One B-rep face of a CAD part: STEP entity #4951.
In plain terms, the planar face has unit normal (0, 1, 0).
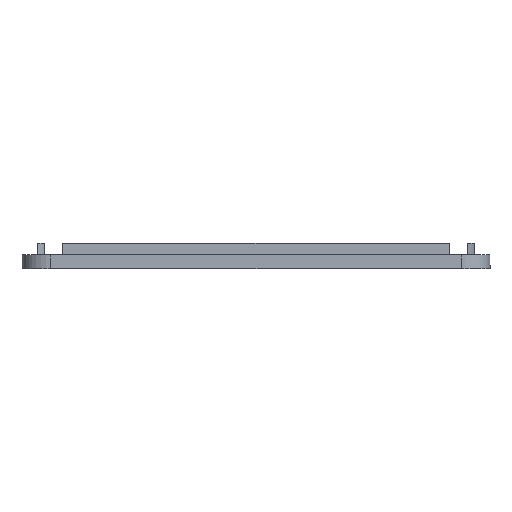
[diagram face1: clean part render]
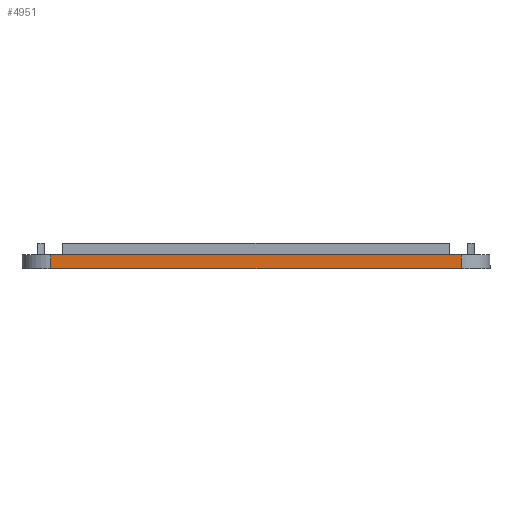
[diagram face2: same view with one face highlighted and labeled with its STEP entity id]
Its self-contained STEP definition (entity closure, numbers rounded to 3 decimals):
#62 = PLANE('',#63);
#63 = AXIS2_PLACEMENT_3D('',#64,#65,#66);
#64 = CARTESIAN_POINT('',(0.,0.,28.));
#65 = DIRECTION('',(0.,0.,1.));
#66 = DIRECTION('',(1.,0.,-0.));
#330 = PLANE('',#331);
#331 = AXIS2_PLACEMENT_3D('',#332,#333,#334);
#332 = CARTESIAN_POINT('',(0.,0.,30.4)
  );
#333 = DIRECTION('',(0.,0.,1.));
#334 = DIRECTION('',(1.,0.,-0.));
#356 = CYLINDRICAL_SURFACE('',#357,5.);
#357 = AXIS2_PLACEMENT_3D('',#358,#359,#360);
#358 = CARTESIAN_POINT('',(-36.,50.,28.));
#359 = DIRECTION('',(0.,0.,-1.));
#360 = DIRECTION('',(-1.,0.,0.));
#490 = VERTEX_POINT('',#491);
#491 = CARTESIAN_POINT('',(36.,55.,28.));
#510 = CYLINDRICAL_SURFACE('',#511,5.);
#511 = AXIS2_PLACEMENT_3D('',#512,#513,#514);
#512 = CARTESIAN_POINT('',(36.,50.,28.));
#513 = DIRECTION('',(0.,0.,-1.));
#514 = DIRECTION('',(-1.,0.,0.));
#522 = EDGE_CURVE('',#523,#490,#525,.T.);
#523 = VERTEX_POINT('',#524);
#524 = CARTESIAN_POINT('',(-36.,55.,28.));
#525 = SURFACE_CURVE('',#526,(#530,#537),.PCURVE_S1.);
#526 = LINE('',#527,#528);
#527 = CARTESIAN_POINT('',(0.,55.,28.));
#528 = VECTOR('',#529,1.);
#529 = DIRECTION('',(1.,0.,0.));
#530 = PCURVE('',#62,#531);
#531 = DEFINITIONAL_REPRESENTATION('',(#532),#536);
#532 = LINE('',#533,#534);
#533 = CARTESIAN_POINT('',(0.,55.));
#534 = VECTOR('',#535,1.);
#535 = DIRECTION('',(1.,0.));
#536 = ( GEOMETRIC_REPRESENTATION_CONTEXT(2) 
PARAMETRIC_REPRESENTATION_CONTEXT() REPRESENTATION_CONTEXT('2D SPACE',''
  ) );
#537 = PCURVE('',#538,#543);
#538 = PLANE('',#539);
#539 = AXIS2_PLACEMENT_3D('',#540,#541,#542);
#540 = CARTESIAN_POINT('',(-36.,55.,28.));
#541 = DIRECTION('',(0.,1.,0.));
#542 = DIRECTION('',(1.,0.,0.));
#543 = DEFINITIONAL_REPRESENTATION('',(#544),#548);
#544 = LINE('',#545,#546);
#545 = CARTESIAN_POINT('',(36.,0.));
#546 = VECTOR('',#547,1.);
#547 = DIRECTION('',(1.,0.));
#548 = ( GEOMETRIC_REPRESENTATION_CONTEXT(2) 
PARAMETRIC_REPRESENTATION_CONTEXT() REPRESENTATION_CONTEXT('2D SPACE',''
  ) );
#2831 = VERTEX_POINT('',#2832);
#2832 = CARTESIAN_POINT('',(-36.,55.,30.4));
#2858 = EDGE_CURVE('',#523,#2831,#2859,.T.);
#2859 = SURFACE_CURVE('',#2860,(#2864,#2871),.PCURVE_S1.);
#2860 = LINE('',#2861,#2862);
#2861 = CARTESIAN_POINT('',(-36.,55.,28.));
#2862 = VECTOR('',#2863,1.);
#2863 = DIRECTION('',(0.,0.,1.));
#2864 = PCURVE('',#356,#2865);
#2865 = DEFINITIONAL_REPRESENTATION('',(#2866),#2870);
#2866 = LINE('',#2867,#2868);
#2867 = CARTESIAN_POINT('',(1.571,0.));
#2868 = VECTOR('',#2869,1.);
#2869 = DIRECTION('',(0.,-1.));
#2870 = ( GEOMETRIC_REPRESENTATION_CONTEXT(2) 
PARAMETRIC_REPRESENTATION_CONTEXT() REPRESENTATION_CONTEXT('2D SPACE',''
  ) );
#2871 = PCURVE('',#538,#2872);
#2872 = DEFINITIONAL_REPRESENTATION('',(#2873),#2877);
#2873 = LINE('',#2874,#2875);
#2874 = CARTESIAN_POINT('',(0.,0.));
#2875 = VECTOR('',#2876,1.);
#2876 = DIRECTION('',(0.,-1.));
#2877 = ( GEOMETRIC_REPRESENTATION_CONTEXT(2) 
PARAMETRIC_REPRESENTATION_CONTEXT() REPRESENTATION_CONTEXT('2D SPACE',''
  ) );
#2929 = VERTEX_POINT('',#2930);
#2930 = CARTESIAN_POINT('',(36.,55.,30.4));
#2956 = EDGE_CURVE('',#2831,#2929,#2957,.T.);
#2957 = SURFACE_CURVE('',#2958,(#2962,#2969),.PCURVE_S1.);
#2958 = LINE('',#2959,#2960);
#2959 = CARTESIAN_POINT('',(0.,55.,30.4));
#2960 = VECTOR('',#2961,1.);
#2961 = DIRECTION('',(1.,0.,0.));
#2962 = PCURVE('',#330,#2963);
#2963 = DEFINITIONAL_REPRESENTATION('',(#2964),#2968);
#2964 = LINE('',#2965,#2966);
#2965 = CARTESIAN_POINT('',(0.,55.));
#2966 = VECTOR('',#2967,1.);
#2967 = DIRECTION('',(1.,0.));
#2968 = ( GEOMETRIC_REPRESENTATION_CONTEXT(2) 
PARAMETRIC_REPRESENTATION_CONTEXT() REPRESENTATION_CONTEXT('2D SPACE',''
  ) );
#2969 = PCURVE('',#538,#2970);
#2970 = DEFINITIONAL_REPRESENTATION('',(#2971),#2975);
#2971 = LINE('',#2972,#2973);
#2972 = CARTESIAN_POINT('',(36.,-2.4));
#2973 = VECTOR('',#2974,1.);
#2974 = DIRECTION('',(1.,0.));
#2975 = ( GEOMETRIC_REPRESENTATION_CONTEXT(2) 
PARAMETRIC_REPRESENTATION_CONTEXT() REPRESENTATION_CONTEXT('2D SPACE',''
  ) );
#4951 = ADVANCED_FACE('',(#4952),#538,.T.);
#4952 = FACE_BOUND('',#4953,.T.);
#4953 = EDGE_LOOP('',(#4954,#4955,#4956,#4977));
#4954 = ORIENTED_EDGE('',*,*,#2858,.T.);
#4955 = ORIENTED_EDGE('',*,*,#2956,.T.);
#4956 = ORIENTED_EDGE('',*,*,#4957,.F.);
#4957 = EDGE_CURVE('',#490,#2929,#4958,.T.);
#4958 = SURFACE_CURVE('',#4959,(#4963,#4970),.PCURVE_S1.);
#4959 = LINE('',#4960,#4961);
#4960 = CARTESIAN_POINT('',(36.,55.,28.));
#4961 = VECTOR('',#4962,1.);
#4962 = DIRECTION('',(0.,0.,1.));
#4963 = PCURVE('',#538,#4964);
#4964 = DEFINITIONAL_REPRESENTATION('',(#4965),#4969);
#4965 = LINE('',#4966,#4967);
#4966 = CARTESIAN_POINT('',(72.,0.));
#4967 = VECTOR('',#4968,1.);
#4968 = DIRECTION('',(0.,-1.));
#4969 = ( GEOMETRIC_REPRESENTATION_CONTEXT(2) 
PARAMETRIC_REPRESENTATION_CONTEXT() REPRESENTATION_CONTEXT('2D SPACE',''
  ) );
#4970 = PCURVE('',#510,#4971);
#4971 = DEFINITIONAL_REPRESENTATION('',(#4972),#4976);
#4972 = LINE('',#4973,#4974);
#4973 = CARTESIAN_POINT('',(1.571,0.));
#4974 = VECTOR('',#4975,1.);
#4975 = DIRECTION('',(0.,-1.));
#4976 = ( GEOMETRIC_REPRESENTATION_CONTEXT(2) 
PARAMETRIC_REPRESENTATION_CONTEXT() REPRESENTATION_CONTEXT('2D SPACE',''
  ) );
#4977 = ORIENTED_EDGE('',*,*,#522,.F.);
